# Generated by FakeRAM 2.0
VERSION 5.7 ;
BUSBITCHARS "[]" ;
PROPERTYDEFINITIONS
  MACRO width INTEGER ;
  MACRO depth INTEGER ;
  MACRO banks INTEGER ;
END PROPERTYDEFINITIONS
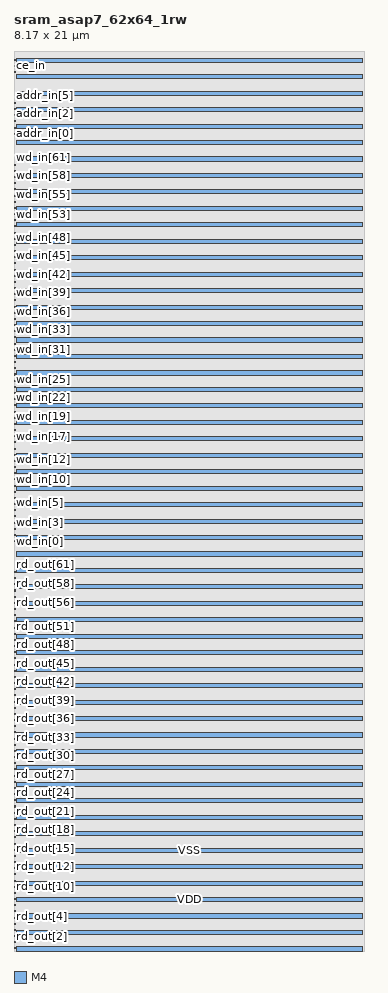
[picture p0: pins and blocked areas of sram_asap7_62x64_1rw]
MACRO sram_asap7_62x64_1rw
  PROPERTY width 62 ;
  PROPERTY depth 64 ;
  PROPERTY banks 1 ;
  FOREIGN sram_asap7_62x64_1rw 0 0 ;
  SYMMETRY X Y R90 ;
  SIZE 8.170 BY 21.000 ;
  CLASS BLOCK ;
  PIN rd_out[0]
    DIRECTION OUTPUT ;
    USE SIGNAL ;
    SHAPE ABUTMENT ;
    PORT
      LAYER M4 ;
      RECT 0.000 0.048 0.024 0.072 ;
    END
  END rd_out[0]
  PIN rd_out[1]
    DIRECTION OUTPUT ;
    USE SIGNAL ;
    SHAPE ABUTMENT ;
    PORT
      LAYER M4 ;
      RECT 0.000 0.192 0.024 0.216 ;
    END
  END rd_out[1]
  PIN rd_out[2]
    DIRECTION OUTPUT ;
    USE SIGNAL ;
    SHAPE ABUTMENT ;
    PORT
      LAYER M4 ;
      RECT 0.000 0.336 0.024 0.360 ;
    END
  END rd_out[2]
  PIN rd_out[3]
    DIRECTION OUTPUT ;
    USE SIGNAL ;
    SHAPE ABUTMENT ;
    PORT
      LAYER M4 ;
      RECT 0.000 0.480 0.024 0.504 ;
    END
  END rd_out[3]
  PIN rd_out[4]
    DIRECTION OUTPUT ;
    USE SIGNAL ;
    SHAPE ABUTMENT ;
    PORT
      LAYER M4 ;
      RECT 0.000 0.624 0.024 0.648 ;
    END
  END rd_out[4]
  PIN rd_out[5]
    DIRECTION OUTPUT ;
    USE SIGNAL ;
    SHAPE ABUTMENT ;
    PORT
      LAYER M4 ;
      RECT 0.000 0.768 0.024 0.792 ;
    END
  END rd_out[5]
  PIN rd_out[6]
    DIRECTION OUTPUT ;
    USE SIGNAL ;
    SHAPE ABUTMENT ;
    PORT
      LAYER M4 ;
      RECT 0.000 0.912 0.024 0.936 ;
    END
  END rd_out[6]
  PIN rd_out[7]
    DIRECTION OUTPUT ;
    USE SIGNAL ;
    SHAPE ABUTMENT ;
    PORT
      LAYER M4 ;
      RECT 0.000 1.056 0.024 1.080 ;
    END
  END rd_out[7]
  PIN rd_out[8]
    DIRECTION OUTPUT ;
    USE SIGNAL ;
    SHAPE ABUTMENT ;
    PORT
      LAYER M4 ;
      RECT 0.000 1.200 0.024 1.224 ;
    END
  END rd_out[8]
  PIN rd_out[9]
    DIRECTION OUTPUT ;
    USE SIGNAL ;
    SHAPE ABUTMENT ;
    PORT
      LAYER M4 ;
      RECT 0.000 1.344 0.024 1.368 ;
    END
  END rd_out[9]
  PIN rd_out[10]
    DIRECTION OUTPUT ;
    USE SIGNAL ;
    SHAPE ABUTMENT ;
    PORT
      LAYER M4 ;
      RECT 0.000 1.488 0.024 1.512 ;
    END
  END rd_out[10]
  PIN rd_out[11]
    DIRECTION OUTPUT ;
    USE SIGNAL ;
    SHAPE ABUTMENT ;
    PORT
      LAYER M4 ;
      RECT 0.000 1.632 0.024 1.656 ;
    END
  END rd_out[11]
  PIN rd_out[12]
    DIRECTION OUTPUT ;
    USE SIGNAL ;
    SHAPE ABUTMENT ;
    PORT
      LAYER M4 ;
      RECT 0.000 1.776 0.024 1.800 ;
    END
  END rd_out[12]
  PIN rd_out[13]
    DIRECTION OUTPUT ;
    USE SIGNAL ;
    SHAPE ABUTMENT ;
    PORT
      LAYER M4 ;
      RECT 0.000 1.920 0.024 1.944 ;
    END
  END rd_out[13]
  PIN rd_out[14]
    DIRECTION OUTPUT ;
    USE SIGNAL ;
    SHAPE ABUTMENT ;
    PORT
      LAYER M4 ;
      RECT 0.000 2.064 0.024 2.088 ;
    END
  END rd_out[14]
  PIN rd_out[15]
    DIRECTION OUTPUT ;
    USE SIGNAL ;
    SHAPE ABUTMENT ;
    PORT
      LAYER M4 ;
      RECT 0.000 2.208 0.024 2.232 ;
    END
  END rd_out[15]
  PIN rd_out[16]
    DIRECTION OUTPUT ;
    USE SIGNAL ;
    SHAPE ABUTMENT ;
    PORT
      LAYER M4 ;
      RECT 0.000 2.352 0.024 2.376 ;
    END
  END rd_out[16]
  PIN rd_out[17]
    DIRECTION OUTPUT ;
    USE SIGNAL ;
    SHAPE ABUTMENT ;
    PORT
      LAYER M4 ;
      RECT 0.000 2.496 0.024 2.520 ;
    END
  END rd_out[17]
  PIN rd_out[18]
    DIRECTION OUTPUT ;
    USE SIGNAL ;
    SHAPE ABUTMENT ;
    PORT
      LAYER M4 ;
      RECT 0.000 2.640 0.024 2.664 ;
    END
  END rd_out[18]
  PIN rd_out[19]
    DIRECTION OUTPUT ;
    USE SIGNAL ;
    SHAPE ABUTMENT ;
    PORT
      LAYER M4 ;
      RECT 0.000 2.784 0.024 2.808 ;
    END
  END rd_out[19]
  PIN rd_out[20]
    DIRECTION OUTPUT ;
    USE SIGNAL ;
    SHAPE ABUTMENT ;
    PORT
      LAYER M4 ;
      RECT 0.000 2.928 0.024 2.952 ;
    END
  END rd_out[20]
  PIN rd_out[21]
    DIRECTION OUTPUT ;
    USE SIGNAL ;
    SHAPE ABUTMENT ;
    PORT
      LAYER M4 ;
      RECT 0.000 3.072 0.024 3.096 ;
    END
  END rd_out[21]
  PIN rd_out[22]
    DIRECTION OUTPUT ;
    USE SIGNAL ;
    SHAPE ABUTMENT ;
    PORT
      LAYER M4 ;
      RECT 0.000 3.216 0.024 3.240 ;
    END
  END rd_out[22]
  PIN rd_out[23]
    DIRECTION OUTPUT ;
    USE SIGNAL ;
    SHAPE ABUTMENT ;
    PORT
      LAYER M4 ;
      RECT 0.000 3.360 0.024 3.384 ;
    END
  END rd_out[23]
  PIN rd_out[24]
    DIRECTION OUTPUT ;
    USE SIGNAL ;
    SHAPE ABUTMENT ;
    PORT
      LAYER M4 ;
      RECT 0.000 3.504 0.024 3.528 ;
    END
  END rd_out[24]
  PIN rd_out[25]
    DIRECTION OUTPUT ;
    USE SIGNAL ;
    SHAPE ABUTMENT ;
    PORT
      LAYER M4 ;
      RECT 0.000 3.648 0.024 3.672 ;
    END
  END rd_out[25]
  PIN rd_out[26]
    DIRECTION OUTPUT ;
    USE SIGNAL ;
    SHAPE ABUTMENT ;
    PORT
      LAYER M4 ;
      RECT 0.000 3.792 0.024 3.816 ;
    END
  END rd_out[26]
  PIN rd_out[27]
    DIRECTION OUTPUT ;
    USE SIGNAL ;
    SHAPE ABUTMENT ;
    PORT
      LAYER M4 ;
      RECT 0.000 3.936 0.024 3.960 ;
    END
  END rd_out[27]
  PIN rd_out[28]
    DIRECTION OUTPUT ;
    USE SIGNAL ;
    SHAPE ABUTMENT ;
    PORT
      LAYER M4 ;
      RECT 0.000 4.080 0.024 4.104 ;
    END
  END rd_out[28]
  PIN rd_out[29]
    DIRECTION OUTPUT ;
    USE SIGNAL ;
    SHAPE ABUTMENT ;
    PORT
      LAYER M4 ;
      RECT 0.000 4.224 0.024 4.248 ;
    END
  END rd_out[29]
  PIN rd_out[30]
    DIRECTION OUTPUT ;
    USE SIGNAL ;
    SHAPE ABUTMENT ;
    PORT
      LAYER M4 ;
      RECT 0.000 4.368 0.024 4.392 ;
    END
  END rd_out[30]
  PIN rd_out[31]
    DIRECTION OUTPUT ;
    USE SIGNAL ;
    SHAPE ABUTMENT ;
    PORT
      LAYER M4 ;
      RECT 0.000 4.512 0.024 4.536 ;
    END
  END rd_out[31]
  PIN rd_out[32]
    DIRECTION OUTPUT ;
    USE SIGNAL ;
    SHAPE ABUTMENT ;
    PORT
      LAYER M4 ;
      RECT 0.000 4.656 0.024 4.680 ;
    END
  END rd_out[32]
  PIN rd_out[33]
    DIRECTION OUTPUT ;
    USE SIGNAL ;
    SHAPE ABUTMENT ;
    PORT
      LAYER M4 ;
      RECT 0.000 4.800 0.024 4.824 ;
    END
  END rd_out[33]
  PIN rd_out[34]
    DIRECTION OUTPUT ;
    USE SIGNAL ;
    SHAPE ABUTMENT ;
    PORT
      LAYER M4 ;
      RECT 0.000 4.944 0.024 4.968 ;
    END
  END rd_out[34]
  PIN rd_out[35]
    DIRECTION OUTPUT ;
    USE SIGNAL ;
    SHAPE ABUTMENT ;
    PORT
      LAYER M4 ;
      RECT 0.000 5.088 0.024 5.112 ;
    END
  END rd_out[35]
  PIN rd_out[36]
    DIRECTION OUTPUT ;
    USE SIGNAL ;
    SHAPE ABUTMENT ;
    PORT
      LAYER M4 ;
      RECT 0.000 5.232 0.024 5.256 ;
    END
  END rd_out[36]
  PIN rd_out[37]
    DIRECTION OUTPUT ;
    USE SIGNAL ;
    SHAPE ABUTMENT ;
    PORT
      LAYER M4 ;
      RECT 0.000 5.376 0.024 5.400 ;
    END
  END rd_out[37]
  PIN rd_out[38]
    DIRECTION OUTPUT ;
    USE SIGNAL ;
    SHAPE ABUTMENT ;
    PORT
      LAYER M4 ;
      RECT 0.000 5.520 0.024 5.544 ;
    END
  END rd_out[38]
  PIN rd_out[39]
    DIRECTION OUTPUT ;
    USE SIGNAL ;
    SHAPE ABUTMENT ;
    PORT
      LAYER M4 ;
      RECT 0.000 5.664 0.024 5.688 ;
    END
  END rd_out[39]
  PIN rd_out[40]
    DIRECTION OUTPUT ;
    USE SIGNAL ;
    SHAPE ABUTMENT ;
    PORT
      LAYER M4 ;
      RECT 0.000 5.808 0.024 5.832 ;
    END
  END rd_out[40]
  PIN rd_out[41]
    DIRECTION OUTPUT ;
    USE SIGNAL ;
    SHAPE ABUTMENT ;
    PORT
      LAYER M4 ;
      RECT 0.000 5.952 0.024 5.976 ;
    END
  END rd_out[41]
  PIN rd_out[42]
    DIRECTION OUTPUT ;
    USE SIGNAL ;
    SHAPE ABUTMENT ;
    PORT
      LAYER M4 ;
      RECT 0.000 6.096 0.024 6.120 ;
    END
  END rd_out[42]
  PIN rd_out[43]
    DIRECTION OUTPUT ;
    USE SIGNAL ;
    SHAPE ABUTMENT ;
    PORT
      LAYER M4 ;
      RECT 0.000 6.240 0.024 6.264 ;
    END
  END rd_out[43]
  PIN rd_out[44]
    DIRECTION OUTPUT ;
    USE SIGNAL ;
    SHAPE ABUTMENT ;
    PORT
      LAYER M4 ;
      RECT 0.000 6.384 0.024 6.408 ;
    END
  END rd_out[44]
  PIN rd_out[45]
    DIRECTION OUTPUT ;
    USE SIGNAL ;
    SHAPE ABUTMENT ;
    PORT
      LAYER M4 ;
      RECT 0.000 6.528 0.024 6.552 ;
    END
  END rd_out[45]
  PIN rd_out[46]
    DIRECTION OUTPUT ;
    USE SIGNAL ;
    SHAPE ABUTMENT ;
    PORT
      LAYER M4 ;
      RECT 0.000 6.672 0.024 6.696 ;
    END
  END rd_out[46]
  PIN rd_out[47]
    DIRECTION OUTPUT ;
    USE SIGNAL ;
    SHAPE ABUTMENT ;
    PORT
      LAYER M4 ;
      RECT 0.000 6.816 0.024 6.840 ;
    END
  END rd_out[47]
  PIN rd_out[48]
    DIRECTION OUTPUT ;
    USE SIGNAL ;
    SHAPE ABUTMENT ;
    PORT
      LAYER M4 ;
      RECT 0.000 6.960 0.024 6.984 ;
    END
  END rd_out[48]
  PIN rd_out[49]
    DIRECTION OUTPUT ;
    USE SIGNAL ;
    SHAPE ABUTMENT ;
    PORT
      LAYER M4 ;
      RECT 0.000 7.104 0.024 7.128 ;
    END
  END rd_out[49]
  PIN rd_out[50]
    DIRECTION OUTPUT ;
    USE SIGNAL ;
    SHAPE ABUTMENT ;
    PORT
      LAYER M4 ;
      RECT 0.000 7.248 0.024 7.272 ;
    END
  END rd_out[50]
  PIN rd_out[51]
    DIRECTION OUTPUT ;
    USE SIGNAL ;
    SHAPE ABUTMENT ;
    PORT
      LAYER M4 ;
      RECT 0.000 7.392 0.024 7.416 ;
    END
  END rd_out[51]
  PIN rd_out[52]
    DIRECTION OUTPUT ;
    USE SIGNAL ;
    SHAPE ABUTMENT ;
    PORT
      LAYER M4 ;
      RECT 0.000 7.536 0.024 7.560 ;
    END
  END rd_out[52]
  PIN rd_out[53]
    DIRECTION OUTPUT ;
    USE SIGNAL ;
    SHAPE ABUTMENT ;
    PORT
      LAYER M4 ;
      RECT 0.000 7.680 0.024 7.704 ;
    END
  END rd_out[53]
  PIN rd_out[54]
    DIRECTION OUTPUT ;
    USE SIGNAL ;
    SHAPE ABUTMENT ;
    PORT
      LAYER M4 ;
      RECT 0.000 7.824 0.024 7.848 ;
    END
  END rd_out[54]
  PIN rd_out[55]
    DIRECTION OUTPUT ;
    USE SIGNAL ;
    SHAPE ABUTMENT ;
    PORT
      LAYER M4 ;
      RECT 0.000 7.968 0.024 7.992 ;
    END
  END rd_out[55]
  PIN rd_out[56]
    DIRECTION OUTPUT ;
    USE SIGNAL ;
    SHAPE ABUTMENT ;
    PORT
      LAYER M4 ;
      RECT 0.000 8.112 0.024 8.136 ;
    END
  END rd_out[56]
  PIN rd_out[57]
    DIRECTION OUTPUT ;
    USE SIGNAL ;
    SHAPE ABUTMENT ;
    PORT
      LAYER M4 ;
      RECT 0.000 8.256 0.024 8.280 ;
    END
  END rd_out[57]
  PIN rd_out[58]
    DIRECTION OUTPUT ;
    USE SIGNAL ;
    SHAPE ABUTMENT ;
    PORT
      LAYER M4 ;
      RECT 0.000 8.400 0.024 8.424 ;
    END
  END rd_out[58]
  PIN rd_out[59]
    DIRECTION OUTPUT ;
    USE SIGNAL ;
    SHAPE ABUTMENT ;
    PORT
      LAYER M4 ;
      RECT 0.000 8.544 0.024 8.568 ;
    END
  END rd_out[59]
  PIN rd_out[60]
    DIRECTION OUTPUT ;
    USE SIGNAL ;
    SHAPE ABUTMENT ;
    PORT
      LAYER M4 ;
      RECT 0.000 8.688 0.024 8.712 ;
    END
  END rd_out[60]
  PIN rd_out[61]
    DIRECTION OUTPUT ;
    USE SIGNAL ;
    SHAPE ABUTMENT ;
    PORT
      LAYER M4 ;
      RECT 0.000 8.832 0.024 8.856 ;
    END
  END rd_out[61]
  PIN wd_in[0]
    DIRECTION INPUT ;
    USE SIGNAL ;
    SHAPE ABUTMENT ;
    PORT
      LAYER M4 ;
      RECT 0.000 9.552 0.024 9.576 ;
    END
  END wd_in[0]
  PIN wd_in[1]
    DIRECTION INPUT ;
    USE SIGNAL ;
    SHAPE ABUTMENT ;
    PORT
      LAYER M4 ;
      RECT 0.000 9.696 0.024 9.720 ;
    END
  END wd_in[1]
  PIN wd_in[2]
    DIRECTION INPUT ;
    USE SIGNAL ;
    SHAPE ABUTMENT ;
    PORT
      LAYER M4 ;
      RECT 0.000 9.840 0.024 9.864 ;
    END
  END wd_in[2]
  PIN wd_in[3]
    DIRECTION INPUT ;
    USE SIGNAL ;
    SHAPE ABUTMENT ;
    PORT
      LAYER M4 ;
      RECT 0.000 9.984 0.024 10.008 ;
    END
  END wd_in[3]
  PIN wd_in[4]
    DIRECTION INPUT ;
    USE SIGNAL ;
    SHAPE ABUTMENT ;
    PORT
      LAYER M4 ;
      RECT 0.000 10.128 0.024 10.152 ;
    END
  END wd_in[4]
  PIN wd_in[5]
    DIRECTION INPUT ;
    USE SIGNAL ;
    SHAPE ABUTMENT ;
    PORT
      LAYER M4 ;
      RECT 0.000 10.272 0.024 10.296 ;
    END
  END wd_in[5]
  PIN wd_in[6]
    DIRECTION INPUT ;
    USE SIGNAL ;
    SHAPE ABUTMENT ;
    PORT
      LAYER M4 ;
      RECT 0.000 10.416 0.024 10.440 ;
    END
  END wd_in[6]
  PIN wd_in[7]
    DIRECTION INPUT ;
    USE SIGNAL ;
    SHAPE ABUTMENT ;
    PORT
      LAYER M4 ;
      RECT 0.000 10.560 0.024 10.584 ;
    END
  END wd_in[7]
  PIN wd_in[8]
    DIRECTION INPUT ;
    USE SIGNAL ;
    SHAPE ABUTMENT ;
    PORT
      LAYER M4 ;
      RECT 0.000 10.704 0.024 10.728 ;
    END
  END wd_in[8]
  PIN wd_in[9]
    DIRECTION INPUT ;
    USE SIGNAL ;
    SHAPE ABUTMENT ;
    PORT
      LAYER M4 ;
      RECT 0.000 10.848 0.024 10.872 ;
    END
  END wd_in[9]
  PIN wd_in[10]
    DIRECTION INPUT ;
    USE SIGNAL ;
    SHAPE ABUTMENT ;
    PORT
      LAYER M4 ;
      RECT 0.000 10.992 0.024 11.016 ;
    END
  END wd_in[10]
  PIN wd_in[11]
    DIRECTION INPUT ;
    USE SIGNAL ;
    SHAPE ABUTMENT ;
    PORT
      LAYER M4 ;
      RECT 0.000 11.136 0.024 11.160 ;
    END
  END wd_in[11]
  PIN wd_in[12]
    DIRECTION INPUT ;
    USE SIGNAL ;
    SHAPE ABUTMENT ;
    PORT
      LAYER M4 ;
      RECT 0.000 11.280 0.024 11.304 ;
    END
  END wd_in[12]
  PIN wd_in[13]
    DIRECTION INPUT ;
    USE SIGNAL ;
    SHAPE ABUTMENT ;
    PORT
      LAYER M4 ;
      RECT 0.000 11.424 0.024 11.448 ;
    END
  END wd_in[13]
  PIN wd_in[14]
    DIRECTION INPUT ;
    USE SIGNAL ;
    SHAPE ABUTMENT ;
    PORT
      LAYER M4 ;
      RECT 0.000 11.568 0.024 11.592 ;
    END
  END wd_in[14]
  PIN wd_in[15]
    DIRECTION INPUT ;
    USE SIGNAL ;
    SHAPE ABUTMENT ;
    PORT
      LAYER M4 ;
      RECT 0.000 11.712 0.024 11.736 ;
    END
  END wd_in[15]
  PIN wd_in[16]
    DIRECTION INPUT ;
    USE SIGNAL ;
    SHAPE ABUTMENT ;
    PORT
      LAYER M4 ;
      RECT 0.000 11.856 0.024 11.880 ;
    END
  END wd_in[16]
  PIN wd_in[17]
    DIRECTION INPUT ;
    USE SIGNAL ;
    SHAPE ABUTMENT ;
    PORT
      LAYER M4 ;
      RECT 0.000 12.000 0.024 12.024 ;
    END
  END wd_in[17]
  PIN wd_in[18]
    DIRECTION INPUT ;
    USE SIGNAL ;
    SHAPE ABUTMENT ;
    PORT
      LAYER M4 ;
      RECT 0.000 12.144 0.024 12.168 ;
    END
  END wd_in[18]
  PIN wd_in[19]
    DIRECTION INPUT ;
    USE SIGNAL ;
    SHAPE ABUTMENT ;
    PORT
      LAYER M4 ;
      RECT 0.000 12.288 0.024 12.312 ;
    END
  END wd_in[19]
  PIN wd_in[20]
    DIRECTION INPUT ;
    USE SIGNAL ;
    SHAPE ABUTMENT ;
    PORT
      LAYER M4 ;
      RECT 0.000 12.432 0.024 12.456 ;
    END
  END wd_in[20]
  PIN wd_in[21]
    DIRECTION INPUT ;
    USE SIGNAL ;
    SHAPE ABUTMENT ;
    PORT
      LAYER M4 ;
      RECT 0.000 12.576 0.024 12.600 ;
    END
  END wd_in[21]
  PIN wd_in[22]
    DIRECTION INPUT ;
    USE SIGNAL ;
    SHAPE ABUTMENT ;
    PORT
      LAYER M4 ;
      RECT 0.000 12.720 0.024 12.744 ;
    END
  END wd_in[22]
  PIN wd_in[23]
    DIRECTION INPUT ;
    USE SIGNAL ;
    SHAPE ABUTMENT ;
    PORT
      LAYER M4 ;
      RECT 0.000 12.864 0.024 12.888 ;
    END
  END wd_in[23]
  PIN wd_in[24]
    DIRECTION INPUT ;
    USE SIGNAL ;
    SHAPE ABUTMENT ;
    PORT
      LAYER M4 ;
      RECT 0.000 13.008 0.024 13.032 ;
    END
  END wd_in[24]
  PIN wd_in[25]
    DIRECTION INPUT ;
    USE SIGNAL ;
    SHAPE ABUTMENT ;
    PORT
      LAYER M4 ;
      RECT 0.000 13.152 0.024 13.176 ;
    END
  END wd_in[25]
  PIN wd_in[26]
    DIRECTION INPUT ;
    USE SIGNAL ;
    SHAPE ABUTMENT ;
    PORT
      LAYER M4 ;
      RECT 0.000 13.296 0.024 13.320 ;
    END
  END wd_in[26]
  PIN wd_in[27]
    DIRECTION INPUT ;
    USE SIGNAL ;
    SHAPE ABUTMENT ;
    PORT
      LAYER M4 ;
      RECT 0.000 13.440 0.024 13.464 ;
    END
  END wd_in[27]
  PIN wd_in[28]
    DIRECTION INPUT ;
    USE SIGNAL ;
    SHAPE ABUTMENT ;
    PORT
      LAYER M4 ;
      RECT 0.000 13.584 0.024 13.608 ;
    END
  END wd_in[28]
  PIN wd_in[29]
    DIRECTION INPUT ;
    USE SIGNAL ;
    SHAPE ABUTMENT ;
    PORT
      LAYER M4 ;
      RECT 0.000 13.728 0.024 13.752 ;
    END
  END wd_in[29]
  PIN wd_in[30]
    DIRECTION INPUT ;
    USE SIGNAL ;
    SHAPE ABUTMENT ;
    PORT
      LAYER M4 ;
      RECT 0.000 13.872 0.024 13.896 ;
    END
  END wd_in[30]
  PIN wd_in[31]
    DIRECTION INPUT ;
    USE SIGNAL ;
    SHAPE ABUTMENT ;
    PORT
      LAYER M4 ;
      RECT 0.000 14.016 0.024 14.040 ;
    END
  END wd_in[31]
  PIN wd_in[32]
    DIRECTION INPUT ;
    USE SIGNAL ;
    SHAPE ABUTMENT ;
    PORT
      LAYER M4 ;
      RECT 0.000 14.160 0.024 14.184 ;
    END
  END wd_in[32]
  PIN wd_in[33]
    DIRECTION INPUT ;
    USE SIGNAL ;
    SHAPE ABUTMENT ;
    PORT
      LAYER M4 ;
      RECT 0.000 14.304 0.024 14.328 ;
    END
  END wd_in[33]
  PIN wd_in[34]
    DIRECTION INPUT ;
    USE SIGNAL ;
    SHAPE ABUTMENT ;
    PORT
      LAYER M4 ;
      RECT 0.000 14.448 0.024 14.472 ;
    END
  END wd_in[34]
  PIN wd_in[35]
    DIRECTION INPUT ;
    USE SIGNAL ;
    SHAPE ABUTMENT ;
    PORT
      LAYER M4 ;
      RECT 0.000 14.592 0.024 14.616 ;
    END
  END wd_in[35]
  PIN wd_in[36]
    DIRECTION INPUT ;
    USE SIGNAL ;
    SHAPE ABUTMENT ;
    PORT
      LAYER M4 ;
      RECT 0.000 14.736 0.024 14.760 ;
    END
  END wd_in[36]
  PIN wd_in[37]
    DIRECTION INPUT ;
    USE SIGNAL ;
    SHAPE ABUTMENT ;
    PORT
      LAYER M4 ;
      RECT 0.000 14.880 0.024 14.904 ;
    END
  END wd_in[37]
  PIN wd_in[38]
    DIRECTION INPUT ;
    USE SIGNAL ;
    SHAPE ABUTMENT ;
    PORT
      LAYER M4 ;
      RECT 0.000 15.024 0.024 15.048 ;
    END
  END wd_in[38]
  PIN wd_in[39]
    DIRECTION INPUT ;
    USE SIGNAL ;
    SHAPE ABUTMENT ;
    PORT
      LAYER M4 ;
      RECT 0.000 15.168 0.024 15.192 ;
    END
  END wd_in[39]
  PIN wd_in[40]
    DIRECTION INPUT ;
    USE SIGNAL ;
    SHAPE ABUTMENT ;
    PORT
      LAYER M4 ;
      RECT 0.000 15.312 0.024 15.336 ;
    END
  END wd_in[40]
  PIN wd_in[41]
    DIRECTION INPUT ;
    USE SIGNAL ;
    SHAPE ABUTMENT ;
    PORT
      LAYER M4 ;
      RECT 0.000 15.456 0.024 15.480 ;
    END
  END wd_in[41]
  PIN wd_in[42]
    DIRECTION INPUT ;
    USE SIGNAL ;
    SHAPE ABUTMENT ;
    PORT
      LAYER M4 ;
      RECT 0.000 15.600 0.024 15.624 ;
    END
  END wd_in[42]
  PIN wd_in[43]
    DIRECTION INPUT ;
    USE SIGNAL ;
    SHAPE ABUTMENT ;
    PORT
      LAYER M4 ;
      RECT 0.000 15.744 0.024 15.768 ;
    END
  END wd_in[43]
  PIN wd_in[44]
    DIRECTION INPUT ;
    USE SIGNAL ;
    SHAPE ABUTMENT ;
    PORT
      LAYER M4 ;
      RECT 0.000 15.888 0.024 15.912 ;
    END
  END wd_in[44]
  PIN wd_in[45]
    DIRECTION INPUT ;
    USE SIGNAL ;
    SHAPE ABUTMENT ;
    PORT
      LAYER M4 ;
      RECT 0.000 16.032 0.024 16.056 ;
    END
  END wd_in[45]
  PIN wd_in[46]
    DIRECTION INPUT ;
    USE SIGNAL ;
    SHAPE ABUTMENT ;
    PORT
      LAYER M4 ;
      RECT 0.000 16.176 0.024 16.200 ;
    END
  END wd_in[46]
  PIN wd_in[47]
    DIRECTION INPUT ;
    USE SIGNAL ;
    SHAPE ABUTMENT ;
    PORT
      LAYER M4 ;
      RECT 0.000 16.320 0.024 16.344 ;
    END
  END wd_in[47]
  PIN wd_in[48]
    DIRECTION INPUT ;
    USE SIGNAL ;
    SHAPE ABUTMENT ;
    PORT
      LAYER M4 ;
      RECT 0.000 16.464 0.024 16.488 ;
    END
  END wd_in[48]
  PIN wd_in[49]
    DIRECTION INPUT ;
    USE SIGNAL ;
    SHAPE ABUTMENT ;
    PORT
      LAYER M4 ;
      RECT 0.000 16.608 0.024 16.632 ;
    END
  END wd_in[49]
  PIN wd_in[50]
    DIRECTION INPUT ;
    USE SIGNAL ;
    SHAPE ABUTMENT ;
    PORT
      LAYER M4 ;
      RECT 0.000 16.752 0.024 16.776 ;
    END
  END wd_in[50]
  PIN wd_in[51]
    DIRECTION INPUT ;
    USE SIGNAL ;
    SHAPE ABUTMENT ;
    PORT
      LAYER M4 ;
      RECT 0.000 16.896 0.024 16.920 ;
    END
  END wd_in[51]
  PIN wd_in[52]
    DIRECTION INPUT ;
    USE SIGNAL ;
    SHAPE ABUTMENT ;
    PORT
      LAYER M4 ;
      RECT 0.000 17.040 0.024 17.064 ;
    END
  END wd_in[52]
  PIN wd_in[53]
    DIRECTION INPUT ;
    USE SIGNAL ;
    SHAPE ABUTMENT ;
    PORT
      LAYER M4 ;
      RECT 0.000 17.184 0.024 17.208 ;
    END
  END wd_in[53]
  PIN wd_in[54]
    DIRECTION INPUT ;
    USE SIGNAL ;
    SHAPE ABUTMENT ;
    PORT
      LAYER M4 ;
      RECT 0.000 17.328 0.024 17.352 ;
    END
  END wd_in[54]
  PIN wd_in[55]
    DIRECTION INPUT ;
    USE SIGNAL ;
    SHAPE ABUTMENT ;
    PORT
      LAYER M4 ;
      RECT 0.000 17.472 0.024 17.496 ;
    END
  END wd_in[55]
  PIN wd_in[56]
    DIRECTION INPUT ;
    USE SIGNAL ;
    SHAPE ABUTMENT ;
    PORT
      LAYER M4 ;
      RECT 0.000 17.616 0.024 17.640 ;
    END
  END wd_in[56]
  PIN wd_in[57]
    DIRECTION INPUT ;
    USE SIGNAL ;
    SHAPE ABUTMENT ;
    PORT
      LAYER M4 ;
      RECT 0.000 17.760 0.024 17.784 ;
    END
  END wd_in[57]
  PIN wd_in[58]
    DIRECTION INPUT ;
    USE SIGNAL ;
    SHAPE ABUTMENT ;
    PORT
      LAYER M4 ;
      RECT 0.000 17.904 0.024 17.928 ;
    END
  END wd_in[58]
  PIN wd_in[59]
    DIRECTION INPUT ;
    USE SIGNAL ;
    SHAPE ABUTMENT ;
    PORT
      LAYER M4 ;
      RECT 0.000 18.048 0.024 18.072 ;
    END
  END wd_in[59]
  PIN wd_in[60]
    DIRECTION INPUT ;
    USE SIGNAL ;
    SHAPE ABUTMENT ;
    PORT
      LAYER M4 ;
      RECT 0.000 18.192 0.024 18.216 ;
    END
  END wd_in[60]
  PIN wd_in[61]
    DIRECTION INPUT ;
    USE SIGNAL ;
    SHAPE ABUTMENT ;
    PORT
      LAYER M4 ;
      RECT 0.000 18.336 0.024 18.360 ;
    END
  END wd_in[61]
  PIN addr_in[0]
    DIRECTION INPUT ;
    USE SIGNAL ;
    SHAPE ABUTMENT ;
    PORT
      LAYER M4 ;
      RECT 0.000 19.056 0.024 19.080 ;
    END
  END addr_in[0]
  PIN addr_in[1]
    DIRECTION INPUT ;
    USE SIGNAL ;
    SHAPE ABUTMENT ;
    PORT
      LAYER M4 ;
      RECT 0.000 19.200 0.024 19.224 ;
    END
  END addr_in[1]
  PIN addr_in[2]
    DIRECTION INPUT ;
    USE SIGNAL ;
    SHAPE ABUTMENT ;
    PORT
      LAYER M4 ;
      RECT 0.000 19.344 0.024 19.368 ;
    END
  END addr_in[2]
  PIN addr_in[3]
    DIRECTION INPUT ;
    USE SIGNAL ;
    SHAPE ABUTMENT ;
    PORT
      LAYER M4 ;
      RECT 0.000 19.488 0.024 19.512 ;
    END
  END addr_in[3]
  PIN addr_in[4]
    DIRECTION INPUT ;
    USE SIGNAL ;
    SHAPE ABUTMENT ;
    PORT
      LAYER M4 ;
      RECT 0.000 19.632 0.024 19.656 ;
    END
  END addr_in[4]
  PIN addr_in[5]
    DIRECTION INPUT ;
    USE SIGNAL ;
    SHAPE ABUTMENT ;
    PORT
      LAYER M4 ;
      RECT 0.000 19.776 0.024 19.800 ;
    END
  END addr_in[5]
  PIN we_in
    DIRECTION INPUT ;
    USE SIGNAL ;
    SHAPE ABUTMENT ;
    PORT
      LAYER M4 ;
      RECT 0.000 20.496 0.024 20.520 ;
    END
  END we_in
  PIN ce_in
    DIRECTION INPUT ;
    USE SIGNAL ;
    SHAPE ABUTMENT ;
    PORT
      LAYER M4 ;
      RECT 0.000 20.640 0.024 20.664 ;
    END
  END ce_in
  PIN clk
    DIRECTION INPUT ;
    USE SIGNAL ;
    SHAPE ABUTMENT ;
    PORT
      LAYER M4 ;
      RECT 0.000 20.784 0.024 20.808 ;
    END
  END clk
  PIN VSS
    DIRECTION INOUT ;
    USE GROUND ;
    PORT
      LAYER M4 ;
      RECT 0.048 0.000 8.122 0.096 ;
      RECT 0.048 0.768 8.122 0.864 ;
      RECT 0.048 1.536 8.122 1.632 ;
      RECT 0.048 2.304 8.122 2.400 ;
      RECT 0.048 3.072 8.122 3.168 ;
      RECT 0.048 3.840 8.122 3.936 ;
      RECT 0.048 4.608 8.122 4.704 ;
      RECT 0.048 5.376 8.122 5.472 ;
      RECT 0.048 6.144 8.122 6.240 ;
      RECT 0.048 6.912 8.122 7.008 ;
      RECT 0.048 7.680 8.122 7.776 ;
      RECT 0.048 8.448 8.122 8.544 ;
      RECT 0.048 9.216 8.122 9.312 ;
      RECT 0.048 9.984 8.122 10.080 ;
      RECT 0.048 10.752 8.122 10.848 ;
      RECT 0.048 11.520 8.122 11.616 ;
      RECT 0.048 12.288 8.122 12.384 ;
      RECT 0.048 13.056 8.122 13.152 ;
      RECT 0.048 13.824 8.122 13.920 ;
      RECT 0.048 14.592 8.122 14.688 ;
      RECT 0.048 15.360 8.122 15.456 ;
      RECT 0.048 16.128 8.122 16.224 ;
      RECT 0.048 16.896 8.122 16.992 ;
      RECT 0.048 17.664 8.122 17.760 ;
      RECT 0.048 18.432 8.122 18.528 ;
      RECT 0.048 19.200 8.122 19.296 ;
      RECT 0.048 19.968 8.122 20.064 ;
      RECT 0.048 20.736 8.122 20.832 ;
    END
  END VSS
  PIN VDD
    DIRECTION INOUT ;
    USE POWER ;
    PORT
      LAYER M4 ;
      RECT 0.048 0.384 8.122 0.480 ;
      RECT 0.048 1.152 8.122 1.248 ;
      RECT 0.048 1.920 8.122 2.016 ;
      RECT 0.048 2.688 8.122 2.784 ;
      RECT 0.048 3.456 8.122 3.552 ;
      RECT 0.048 4.224 8.122 4.320 ;
      RECT 0.048 4.992 8.122 5.088 ;
      RECT 0.048 5.760 8.122 5.856 ;
      RECT 0.048 6.528 8.122 6.624 ;
      RECT 0.048 7.296 8.122 7.392 ;
      RECT 0.048 8.064 8.122 8.160 ;
      RECT 0.048 8.832 8.122 8.928 ;
      RECT 0.048 9.600 8.122 9.696 ;
      RECT 0.048 10.368 8.122 10.464 ;
      RECT 0.048 11.136 8.122 11.232 ;
      RECT 0.048 11.904 8.122 12.000 ;
      RECT 0.048 12.672 8.122 12.768 ;
      RECT 0.048 13.440 8.122 13.536 ;
      RECT 0.048 14.208 8.122 14.304 ;
      RECT 0.048 14.976 8.122 15.072 ;
      RECT 0.048 15.744 8.122 15.840 ;
      RECT 0.048 16.512 8.122 16.608 ;
      RECT 0.048 17.280 8.122 17.376 ;
      RECT 0.048 18.048 8.122 18.144 ;
      RECT 0.048 18.816 8.122 18.912 ;
      RECT 0.048 19.584 8.122 19.680 ;
      RECT 0.048 20.352 8.122 20.448 ;
    END
  END VDD
  OBS
    LAYER M1 ;
    RECT 0 0 8.170 21.000 ;
    LAYER M2 ;
    RECT 0 0 8.170 21.000 ;
    LAYER M3 ;
    RECT 0 0 8.170 21.000 ;
    LAYER M4 ;
    RECT 0 0 8.170 21.000 ;
  END
END sram_asap7_62x64_1rw

END LIBRARY
